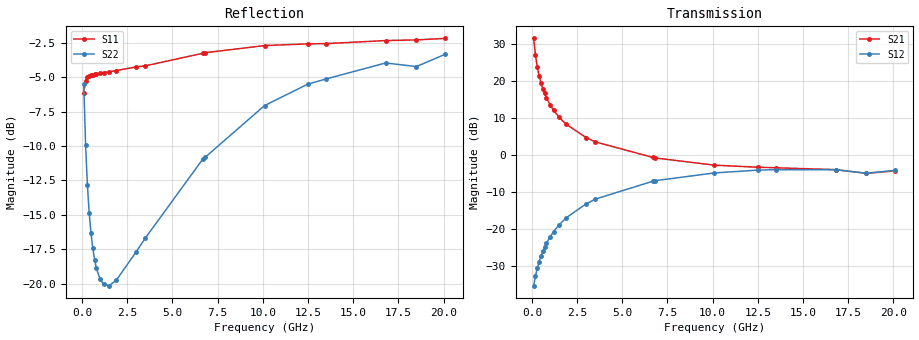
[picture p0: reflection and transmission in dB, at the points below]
!  Infineon Technologies AG
! BFR380L3 , PF131585-7, No.6, Th 09.10.01, soldered on pcb-board, measured with PP GSG850
!  Vce=3.0 V,  Ic=80.0 mA
! Common Emitter S-Parameters:  15. November 2001
#  GHz  S  MA  R  50
! f  S11  S21  S12  S22
! GHz  Mag  Ang  Mag  Ang  Mag  Ang  Mag  Ang
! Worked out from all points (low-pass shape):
!   201 points, 100 MHz to 20.1 GHz, reference 50 ohm
!   highest |S21| = 31.42 dB at 100 MHz (marker M1); lowest = -5.0 dB at 18.5 GHz (marker M2)
!   |S21| within 3 dB of the highest: start of sweep to 165.4 MHz
!   lowest |S11| = -6.2 dB at 100 MHz (marker M3), VSWR 2.93, Z = 22.3 - j25.6 ohm
!   |S11| at or under -10 dB: nowhere
!   |S22| runs from -20.1 to -3.3 dB; largest |S21 - S12| = 37
!   S11 on the Smith chart (normalised r, x): 100 MHz: 0.45, -0.51; 500 MHz: 0.27, -0.06; 3 GHz: 0.27, +0.33; 6.7 GHz: 0.31, +0.80; 12.5 GHz: 0.53, +1.55; 20.1 GHz: 1.09, +2.58
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0.1  0.4916 -117.7  37.25 126.7  0.01719 56.2  0.5303 -54.0
0.2  0.5467 -147.6  21.96 108.4  0.02342 56.5  0.3195 -73.2
0.3  0.5633 -160.1  15.25 100.3  0.02984 61.5  0.2283 -82.4
0.4  0.5674 -167.3  11.62 95.1  0.03617 64.1  0.1809 -88.7
0.5  0.5707 -172.4  9.368 91.4  0.04292 66.5  0.1526 -93.5
0.6  0.5728 -176.2  7.848 88.5  0.04976 67.9  0.1344 -97.5
0.7  0.5761 -179.4  6.758 85.8  0.0567 69.0  0.1222 -101.2
0.8  0.5772 178.0  5.933 83.4  0.06388 69.9  0.1137 -104.5
1  0.5803 173.3  4.776 79.3  0.07797 70.5  0.1039 -110.3
1.2  0.5843 169.2  4.001 75.5  0.09211 70.4  0.09974 -115.3
1.5  0.5876 163.8  3.232 70.3  0.1133 69.8  0.09838 -122.0
1.9  0.5943 157.5  2.586 63.9  0.1419 68.2  0.103 -129.9
3  0.6123 141.1  1.714 48.0  0.218 61.7  0.1306 -148.6
3.5  0.618 134.4  1.499 41.6  0.2524 58.3  0.1463 -154.8
6.7  0.6867 99.4  0.9216 10.6  0.4414 35.1  0.2844 161.1
6.8  0.6895 98.5  0.9101 9.8  0.4474 34.3  0.2873 159.9
10.1  0.732 74.0  0.7259 -8.3  0.5703 11.4  0.4434 126.5
12.5  0.7426 61.6  0.6808 -18.1  0.6222 -3.9  0.5306 105.2
13.5  0.7442 57.2  0.669 -22.2  0.6305 -9.9  0.5538 98.0
16.8  0.7635 45.8  0.6319 -32.8  0.6298 -25.9  0.6331 76.6
18.5  0.7676 43.9  0.5626 -40.2  0.5653 -34.1  0.6143 71.3
20.1  0.7776 37.1  0.6087 -43.6  0.619 -39.4  0.6812 60.3
